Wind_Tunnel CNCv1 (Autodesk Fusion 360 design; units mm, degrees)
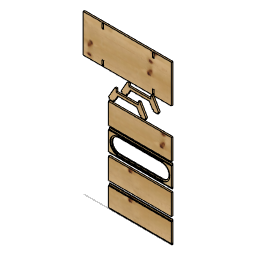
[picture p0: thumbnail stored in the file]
named bodies: "Front", "Top", "Bottom", "Back", "Stand legs1", "Stand legs2", "platform"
